VERSION 5.7 ;
  NOWIREEXTENSIONATPIN ON ;
  DIVIDERCHAR "/" ;
  BUSBITCHARS "[]" ;
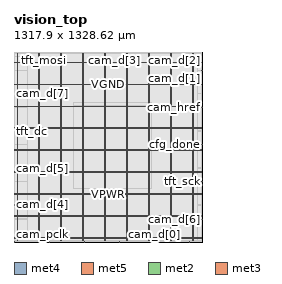
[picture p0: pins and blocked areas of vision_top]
MACRO vision_top
  CLASS BLOCK ;
  FOREIGN vision_top ;
  ORIGIN 0.000 0.000 ;
  SIZE 1317.905 BY 1328.625 ;
  PIN VGND
    DIRECTION INOUT ;
    USE GROUND ;
    PORT
      LAYER met4 ;
        RECT 24.340 10.640 25.940 1316.720 ;
    END
    PORT
      LAYER met4 ;
        RECT 177.940 10.640 179.540 1316.720 ;
    END
    PORT
      LAYER met4 ;
        RECT 331.540 10.640 333.140 1316.720 ;
    END
    PORT
      LAYER met4 ;
        RECT 485.140 10.640 486.740 1316.720 ;
    END
    PORT
      LAYER met4 ;
        RECT 638.740 10.640 640.340 1316.720 ;
    END
    PORT
      LAYER met4 ;
        RECT 792.340 10.640 793.940 1316.720 ;
    END
    PORT
      LAYER met4 ;
        RECT 945.940 10.640 947.540 1316.720 ;
    END
    PORT
      LAYER met4 ;
        RECT 1099.540 10.640 1101.140 1316.720 ;
    END
    PORT
      LAYER met4 ;
        RECT 1253.140 10.640 1254.740 1316.720 ;
    END
    PORT
      LAYER met5 ;
        RECT 5.280 30.030 1312.620 31.630 ;
    END
    PORT
      LAYER met5 ;
        RECT 5.280 183.210 1312.620 184.810 ;
    END
    PORT
      LAYER met5 ;
        RECT 5.280 336.390 1312.620 337.990 ;
    END
    PORT
      LAYER met5 ;
        RECT 5.280 489.570 1312.620 491.170 ;
    END
    PORT
      LAYER met5 ;
        RECT 5.280 642.750 1312.620 644.350 ;
    END
    PORT
      LAYER met5 ;
        RECT 5.280 795.930 1312.620 797.530 ;
    END
    PORT
      LAYER met5 ;
        RECT 5.280 949.110 1312.620 950.710 ;
    END
    PORT
      LAYER met5 ;
        RECT 5.280 1102.290 1312.620 1103.890 ;
    END
    PORT
      LAYER met5 ;
        RECT 5.280 1255.470 1312.620 1257.070 ;
    END
  END VGND
  PIN VPWR
    DIRECTION INOUT ;
    USE POWER ;
    PORT
      LAYER met4 ;
        RECT 21.040 10.640 22.640 1316.720 ;
    END
    PORT
      LAYER met4 ;
        RECT 174.640 10.640 176.240 1316.720 ;
    END
    PORT
      LAYER met4 ;
        RECT 328.240 10.640 329.840 1316.720 ;
    END
    PORT
      LAYER met4 ;
        RECT 481.840 10.640 483.440 1316.720 ;
    END
    PORT
      LAYER met4 ;
        RECT 635.440 10.640 637.040 1316.720 ;
    END
    PORT
      LAYER met4 ;
        RECT 789.040 10.640 790.640 1316.720 ;
    END
    PORT
      LAYER met4 ;
        RECT 942.640 10.640 944.240 1316.720 ;
    END
    PORT
      LAYER met4 ;
        RECT 1096.240 10.640 1097.840 1316.720 ;
    END
    PORT
      LAYER met4 ;
        RECT 1249.840 10.640 1251.440 1316.720 ;
    END
    PORT
      LAYER met5 ;
        RECT 5.280 26.730 1312.620 28.330 ;
    END
    PORT
      LAYER met5 ;
        RECT 5.280 179.910 1312.620 181.510 ;
    END
    PORT
      LAYER met5 ;
        RECT 5.280 333.090 1312.620 334.690 ;
    END
    PORT
      LAYER met5 ;
        RECT 5.280 486.270 1312.620 487.870 ;
    END
    PORT
      LAYER met5 ;
        RECT 5.280 639.450 1312.620 641.050 ;
    END
    PORT
      LAYER met5 ;
        RECT 5.280 792.630 1312.620 794.230 ;
    END
    PORT
      LAYER met5 ;
        RECT 5.280 945.810 1312.620 947.410 ;
    END
    PORT
      LAYER met5 ;
        RECT 5.280 1098.990 1312.620 1100.590 ;
    END
    PORT
      LAYER met5 ;
        RECT 5.280 1252.170 1312.620 1253.770 ;
    END
  END VPWR
  PIN cam_d[0]
    DIRECTION INPUT ;
    USE SIGNAL ;
    ANTENNAGATEAREA 0.495000 ;
    PORT
      LAYER met2 ;
        RECT 982.190 0.000 982.470 4.000 ;
    END
  END cam_d[0]
  PIN cam_d[1]
    DIRECTION INPUT ;
    USE SIGNAL ;
    ANTENNAGATEAREA 0.213000 ;
    PORT
      LAYER met3 ;
        RECT 1313.905 1196.840 1317.905 1197.440 ;
    END
  END cam_d[1]
  PIN cam_d[2]
    DIRECTION INPUT ;
    USE SIGNAL ;
    ANTENNAGATEAREA 0.159000 ;
    PORT
      LAYER met2 ;
        RECT 1194.710 1324.625 1194.990 1328.625 ;
    END
  END cam_d[2]
  PIN cam_d[3]
    DIRECTION INPUT ;
    USE SIGNAL ;
    ANTENNAGATEAREA 0.159000 ;
    PORT
      LAYER met2 ;
        RECT 705.270 1324.625 705.550 1328.625 ;
    END
  END cam_d[3]
  PIN cam_d[4]
    DIRECTION INPUT ;
    USE SIGNAL ;
    ANTENNAGATEAREA 0.990000 ;
    PORT
      LAYER met3 ;
        RECT 0.000 258.440 4.000 259.040 ;
    END
  END cam_d[4]
  PIN cam_d[5]
    DIRECTION INPUT ;
    USE SIGNAL ;
    ANTENNAGATEAREA 0.852000 ;
    PORT
      LAYER met3 ;
        RECT 0.000 516.840 4.000 517.440 ;
    END
  END cam_d[5]
  PIN cam_d[6]
    DIRECTION INPUT ;
    USE SIGNAL ;
    ANTENNAGATEAREA 0.742500 ;
    PORT
      LAYER met3 ;
        RECT 1313.905 159.840 1317.905 160.440 ;
    END
  END cam_d[6]
  PIN cam_d[7]
    DIRECTION INPUT ;
    USE SIGNAL ;
    ANTENNAGATEAREA 0.495000 ;
    PORT
      LAYER met3 ;
        RECT 0.000 1037.040 4.000 1037.640 ;
    END
  END cam_d[7]
  PIN cam_href
    DIRECTION INPUT ;
    USE SIGNAL ;
    ANTENNAGATEAREA 0.247500 ;
    PORT
      LAYER met3 ;
        RECT 1313.905 938.440 1317.905 939.040 ;
    END
  END cam_href
  PIN cam_pclk
    DIRECTION INPUT ;
    USE SIGNAL ;
    ANTENNAGATEAREA 1.286700 ;
    ANTENNADIFFAREA 0.434700 ;
    PORT
      LAYER met2 ;
        RECT 0.090 0.000 0.370 4.000 ;
    END
  END cam_pclk
  PIN cam_scl
    DIRECTION OUTPUT TRISTATE ;
    USE SIGNAL ;
    ANTENNADIFFAREA 0.340600 ;
    PORT
      LAYER met2 ;
        RECT 244.810 0.000 245.090 4.000 ;
    END
  END cam_scl
  PIN cam_sda_o
    DIRECTION OUTPUT TRISTATE ;
    USE SIGNAL ;
    PORT
      LAYER met2 ;
        RECT 1226.910 0.000 1227.190 4.000 ;
    END
  END cam_sda_o
  PIN cam_sda_oe
    DIRECTION OUTPUT TRISTATE ;
    USE SIGNAL ;
    ANTENNADIFFAREA 0.340600 ;
    PORT
      LAYER met2 ;
        RECT 489.530 0.000 489.810 4.000 ;
    END
  END cam_sda_oe
  PIN cam_xclk
    DIRECTION OUTPUT TRISTATE ;
    USE SIGNAL ;
    ANTENNADIFFAREA 0.340600 ;
    PORT
      LAYER met2 ;
        RECT 457.330 1324.625 457.610 1328.625 ;
    END
  END cam_xclk
  PIN cfg_done
    DIRECTION OUTPUT TRISTATE ;
    USE SIGNAL ;
    ANTENNADIFFAREA 0.340600 ;
    PORT
      LAYER met3 ;
        RECT 1313.905 680.040 1317.905 680.640 ;
    END
  END cfg_done
  PIN clk
    DIRECTION INPUT ;
    USE SIGNAL ;
    ANTENNAGATEAREA 1.721400 ;
    ANTENNADIFFAREA 0.869400 ;
    PORT
      LAYER met3 ;
        RECT 0.000 1295.440 4.000 1296.040 ;
    END
  END clk
  PIN rst_n
    DIRECTION INPUT ;
    USE SIGNAL ;
    ANTENNAGATEAREA 0.990000 ;
    PORT
      LAYER met2 ;
        RECT 949.990 1324.625 950.270 1328.625 ;
    END
  END rst_n
  PIN tft_cs
    DIRECTION OUTPUT TRISTATE ;
    USE SIGNAL ;
    ANTENNADIFFAREA 0.340600 ;
    PORT
      LAYER met2 ;
        RECT 734.250 0.000 734.530 4.000 ;
    END
  END tft_cs
  PIN tft_dc
    DIRECTION OUTPUT TRISTATE ;
    USE SIGNAL ;
    ANTENNADIFFAREA 0.340600 ;
    PORT
      LAYER met3 ;
        RECT 0.000 775.240 4.000 775.840 ;
    END
  END tft_dc
  PIN tft_mosi
    DIRECTION OUTPUT TRISTATE ;
    USE SIGNAL ;
    ANTENNADIFFAREA 0.340600 ;
    PORT
      LAYER met2 ;
        RECT 212.610 1324.625 212.890 1328.625 ;
    END
  END tft_mosi
  PIN tft_sck
    DIRECTION OUTPUT TRISTATE ;
    USE SIGNAL ;
    ANTENNADIFFAREA 0.340600 ;
    PORT
      LAYER met3 ;
        RECT 1313.905 421.640 1317.905 422.240 ;
    END
  END tft_sck
  OBS
      LAYER li1 ;
        RECT 5.520 10.795 1312.380 1316.565 ;
      LAYER met1 ;
        RECT 4.670 10.640 1312.770 1316.720 ;
      LAYER met2 ;
        RECT 0.090 1324.345 212.330 1324.625 ;
        RECT 213.170 1324.345 457.050 1324.625 ;
        RECT 457.890 1324.345 704.990 1324.625 ;
        RECT 705.830 1324.345 949.710 1324.625 ;
        RECT 950.550 1324.345 1194.430 1324.625 ;
        RECT 1195.270 1324.345 1312.750 1324.625 ;
        RECT 0.090 4.280 1312.750 1324.345 ;
        RECT 0.650 4.000 244.530 4.280 ;
        RECT 245.370 4.000 489.250 4.280 ;
        RECT 490.090 4.000 733.970 4.280 ;
        RECT 734.810 4.000 981.910 4.280 ;
        RECT 982.750 4.000 1226.630 4.280 ;
        RECT 1227.470 4.000 1312.750 4.280 ;
      LAYER met3 ;
        RECT 0.065 1296.440 1313.905 1316.645 ;
        RECT 4.400 1295.040 1313.905 1296.440 ;
        RECT 0.065 1197.840 1313.905 1295.040 ;
        RECT 0.065 1196.440 1313.505 1197.840 ;
        RECT 0.065 1038.040 1313.905 1196.440 ;
        RECT 4.400 1036.640 1313.905 1038.040 ;
        RECT 0.065 939.440 1313.905 1036.640 ;
        RECT 0.065 938.040 1313.505 939.440 ;
        RECT 0.065 776.240 1313.905 938.040 ;
        RECT 4.400 774.840 1313.905 776.240 ;
        RECT 0.065 681.040 1313.905 774.840 ;
        RECT 0.065 679.640 1313.505 681.040 ;
        RECT 0.065 517.840 1313.905 679.640 ;
        RECT 4.400 516.440 1313.905 517.840 ;
        RECT 0.065 422.640 1313.905 516.440 ;
        RECT 0.065 421.240 1313.505 422.640 ;
        RECT 0.065 259.440 1313.905 421.240 ;
        RECT 4.400 258.040 1313.905 259.440 ;
        RECT 0.065 160.840 1313.905 258.040 ;
        RECT 0.065 159.440 1313.505 160.840 ;
        RECT 0.065 10.715 1313.905 159.440 ;
      LAYER met4 ;
        RECT 95.975 13.095 174.240 1314.945 ;
        RECT 176.640 13.095 177.540 1314.945 ;
        RECT 179.940 13.095 327.840 1314.945 ;
        RECT 330.240 13.095 331.140 1314.945 ;
        RECT 333.540 13.095 481.440 1314.945 ;
        RECT 483.840 13.095 484.740 1314.945 ;
        RECT 487.140 13.095 635.040 1314.945 ;
        RECT 637.440 13.095 638.340 1314.945 ;
        RECT 640.740 13.095 788.640 1314.945 ;
        RECT 791.040 13.095 791.940 1314.945 ;
        RECT 794.340 13.095 942.240 1314.945 ;
        RECT 944.640 13.095 945.540 1314.945 ;
        RECT 947.940 13.095 1095.840 1314.945 ;
        RECT 1098.240 13.095 1099.140 1314.945 ;
        RECT 1101.540 13.095 1249.440 1314.945 ;
        RECT 1251.840 13.095 1252.740 1314.945 ;
        RECT 1255.140 13.095 1282.185 1314.945 ;
      LAYER met5 ;
        RECT 412.740 952.310 964.500 978.300 ;
        RECT 412.740 799.130 964.500 944.210 ;
        RECT 412.740 645.950 964.500 791.030 ;
        RECT 412.740 492.770 964.500 637.850 ;
        RECT 412.740 371.500 964.500 484.670 ;
  END
END vision_top
END LIBRARY

